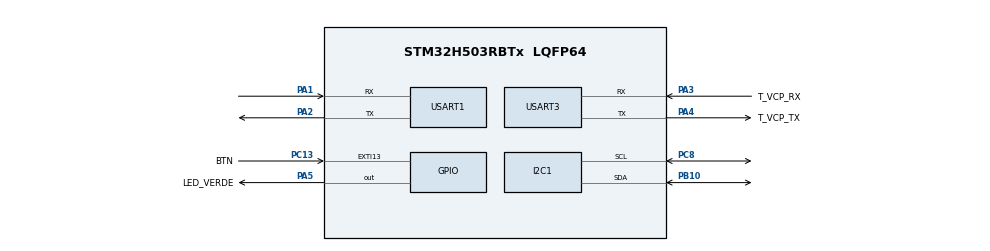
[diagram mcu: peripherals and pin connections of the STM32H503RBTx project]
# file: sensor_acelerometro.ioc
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BOOTPATH.BootPathName=LEGACY
BOOTPATH.UserSelectedBootPath=LEGACY
I2C1.Timing=0x10707DBC
Mcu.Family=STM32H5
Mcu.Name=STM32H503RBTx
Mcu.Package=LQFP64
NVIC.I2C1_ER_IRQn=true\:0\:0\:false\:false\:true\:true\:true\:true
NVIC.I2C1_EV_IRQn=true\:0\:0\:false\:false\:true\:true\:true\:true
NVIC.PriorityGroup=NVIC_PRIORITYGROUP_4
PA1.Mode=Asynchronous
PA1.Signal=USART1_RX
PA2.Mode=Asynchronous
PA2.Signal=USART1_TX
PA3.GPIO_Label=T_VCP_RX
PA3.Mode=Asynchronous
PA3.Signal=USART3_RX
PA4.GPIO_Label=T_VCP_TX
PA4.Mode=Asynchronous
PA4.Signal=USART3_TX
PA5.GPIO_Label=LED_VERDE
PA5.Signal=GPIO_Output
PB10.Mode=I2C
PB10.Signal=I2C1_SDA
PC13.GPIO_Label=BTN
PC13.Signal=GPXTI13
PC8.Mode=I2C
PC8.Signal=I2C1_SCL
ProjectManager.HeapSize=0x200
ProjectManager.StackSize=0x400
ProjectManager.TargetToolchain=STM32CubeIDE
RCC.ADCFreq_Value=64000000
RCC.AHBFreq_Value=64000000
RCC.APB1Freq_Value=64000000
RCC.APB1TimFreq_Value=64000000
RCC.APB2Freq_Value=64000000
RCC.APB2TimFreq_Value=64000000
RCC.APB3Freq_Value=64000000
RCC.CSI_VALUE=4000000
RCC.CortexFreq_Value=64000000
RCC.EPOD_VALUE=4000000
RCC.HCLKFreq_Value=64000000
RCC.HSE_VALUE=24000000
RCC.HSI48_VALUE=48000000
RCC.HSIDiv=RCC_HSI_DIV1
RCC.HSI_VALUE=64000000
RCC.LSE_VALUE=32768
RCC.LSIRC_VALUE=32000
RCC.PLLN=32
RCC.SYSCLKFreq_VALUE=64000000
RCC.USBFreq_Value=48000000
RCC.VCOOutputFreq_Value=128000000
USART1.VirtualMode-Asynchronous=VM_ASYNC
USART3.VirtualMode-Asynchronous=VM_ASYNC
VP_BOOTPATH_VS_BOOTPATH.Mode=BP_Activate
VP_CORTEX_M33_NS_VS_Hclk.Mode=Hclk_Mode
VP_MEMORYMAP_VS_MEMORYMAP.Mode=CurAppReg
VP_PWR_VS_DBSignals.Mode=DisableDeadBatterySignals
VP_PWR_VS_LPOM.Mode=PowerOptimisation
VP_PWR_VS_SECSignals.Mode=Security/Privilege
board=NUCLEO-H503RB

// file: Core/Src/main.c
/* USER CODE BEGIN Header */
/**
  ******************************************************************************
  * @file           : main.c
  * @brief          : Main program body
  ******************************************************************************
  * @attention
  *
  * Copyright (c) 2025 STMicroelectronics.
  * All rights reserved.
  *
  * This software is licensed under terms that can be found in the LICENSE file
  * in the root directory of this software component.
  * If no LICENSE file comes with this software, it is provided AS-IS.
  *
  ******************************************************************************
  */
/* USER CODE END Header */
#include "main.h"

/* USER CODE BEGIN Includes */
#include "stdbool.h"
/* USER CODE END Includes */

/* USER CODE BEGIN PTD */
#define BUFFER_MAX_USART 100

#define ADXL345_ADDR       0x53<<1  //Dirección I2C
#define REG_DEVID          0x00
#define REG_POWER_CTL      0x2D
#define REG_DATA_FORMAT    0x31
#define REG_BW_RATE        0x2C
#define REG_DATAX0         0x32
#define REG_DATAX1         0x33
#define REG_DATAY0         0x34
#define REG_DATAY1         0x35
#define REG_DATAZ0         0x36
#define REG_DATAZ1         0x37

#define REG_THRESH_ACT     0x24
#define REG_INT_ENABLE     0x2E
#define REG_INT_SOURCE     0x30

typedef struct{
	uint8_t bytes [BUFFER_MAX_USART];
	uint16_t longitud;
}Transfer_Config;

typedef struct{
	volatile float x_axis;
	volatile float y_axis;
	volatile float z_axis;
	volatile float acelX_filtrada;
	volatile float acelY_filtrada;
	volatile float acelZ_filtrada;
	bool startMeasure;
} Device_Config;

typedef struct{
	uint8_t ID;
	bool deviceReady;
	uint8_t rawData[8];
	int16_t rawX;
	int16_t rawY;
	int16_t rawZ;
} ADXL_Config;

typedef struct{
	uint8_t data_format;
	uint8_t power_ctl;
	uint8_t bw_rate;
} Values_ADXL;

Device_Config datos={};
ADXL_Config acelerometro={};
Values_ADXL values={};
Transfer_Config tx={};

void ADXL_Init(void);
void Value_Conversion(void);
void Send_USART(void);
float filtroSuavizado(float nuevo, float anterior);

/* USER CODE END PTD */

I2C_HandleTypeDef hi2c1;

UART_HandleTypeDef huart1;
UART_HandleTypeDef huart3;

void SystemClock_Config(void);
static void MX_GPIO_Init(void);
static void MX_I2C1_Init(void);
static void MX_USART3_UART_Init(void);
static void MX_USART1_UART_Init(void);

int main(void)
{

  /* MCU Configuration--------------------------------------------------------*/

  /* Reset of all peripherals, Initializes the Flash interface and the Systick. */
  HAL_Init();

  /* Configure the system clock */
  SystemClock_Config();

  /* Initialize all configured peripherals */
  MX_GPIO_Init();
  MX_I2C1_Init();
  MX_USART3_UART_Init();
  MX_USART1_UART_Init();
  /* USER CODE BEGIN 2 */

  datos.startMeasure=false;
  datos.x_axis=0;
  datos.y_axis=0;
  datos.z_axis=0;
  datos.acelX_filtrada=0;
  datos.acelY_filtrada=0;
  datos.acelZ_filtrada=0;

  //confirmacion de que existe acelerometro
  HAL_I2C_Mem_Read(&hi2c1, ADXL345_ADDR, REG_DEVID, 1, &acelerometro.ID, 1, 100);
  if (acelerometro.ID==0xE5) {
	  acelerometro.deviceReady=true;
  } else{
	  acelerometro.deviceReady=false;
  }

  //configuracion de acelerometro
  if(acelerometro.deviceReady){
	  ADXL_Init();
  }

  /* USER CODE END 2 */

  /* Infinite loop */
  /* USER CODE BEGIN WHILE */
  while (1)
  {
	  //obtencion de datos crudos
	    uint8_t buffer[2];

	    // Leer X
	    HAL_I2C_Mem_Read(&hi2c1, ADXL345_ADDR, REG_DATAX0, 1, buffer, 2, 100);
	    acelerometro.rawX = (buffer[1] << 8 | buffer[0]);

	    // Leer Y
	    HAL_I2C_Mem_Read(&hi2c1, ADXL345_ADDR, REG_DATAY0, 1, buffer, 2, 100);
	    acelerometro.rawY =(buffer[1] << 8 | buffer[0]);

	    //Leer Z
	    HAL_I2C_Mem_Read(&hi2c1, ADXL345_ADDR, REG_DATAZ0, 1, buffer, 2, 100);
	    acelerometro.rawZ = (buffer[1] << 8 | buffer[0]);

	    Value_Conversion();
	    Send_USART();

	    datos.acelX_filtrada = filtroSuavizado(datos.x_axis, datos.acelX_filtrada);
	    datos.acelY_filtrada = filtroSuavizado(datos.y_axis, datos.acelY_filtrada);
	    datos.acelZ_filtrada = filtroSuavizado(datos.z_axis, datos.acelZ_filtrada);

	    float magnitud = sqrt(pow(datos.acelX_filtrada,2) + pow(datos.acelY_filtrada,2) + pow(datos.acelZ_filtrada,2));

	    if (magnitud > 1.3 && magnitud < 2.0) {
	        snprintf((char*)tx.bytes, sizeof(tx.bytes), "Temblor leve detectado\r\n");
	        HAL_UART_Transmit(&huart3, tx.bytes, strlen((char*)tx.bytes), 1000);
	        HAL_UART_Transmit(&huart1, tx.bytes, strlen((char*)tx.bytes), 1000);

	    }
	    else if (magnitud >= 2.0) {
	        snprintf((char*)tx.bytes, sizeof(tx.bytes), "Temblor fuerte detectado\r\n");
	        HAL_UART_Transmit(&huart3, tx.bytes, strlen((char*)tx.bytes), 1000);
	        HAL_UART_Transmit(&huart1, tx.bytes, strlen((char*)tx.bytes), 1000);
	    }

    /* USER CODE END WHILE */

  }
}

void SystemClock_Config(void)
{
  RCC_OscInitTypeDef RCC_OscInitStruct = {0};
  RCC_ClkInitTypeDef RCC_ClkInitStruct = {0};

  /** Configure the main internal regulator output voltage
  */
  __HAL_PWR_VOLTAGESCALING_CONFIG(PWR_REGULATOR_VOLTAGE_SCALE3);

  while(!__HAL_PWR_GET_FLAG(PWR_FLAG_VOSRDY)) {}

  /** Initializes the RCC Oscillators according to the specified parameters
  * in the RCC_OscInitTypeDef structure.
  */
  RCC_OscInitStruct.OscillatorType = RCC_OSCILLATORTYPE_CSI;
  RCC_OscInitStruct.CSIState = RCC_CSI_ON;
  RCC_OscInitStruct.CSICalibrationValue = RCC_CSICALIBRATION_DEFAULT;
  RCC_OscInitStruct.PLL.PLLState = RCC_PLL_ON;
  RCC_OscInitStruct.PLL.PLLSource = RCC_PLL1_SOURCE_CSI;
  RCC_OscInitStruct.PLL.PLLM = 1;
  RCC_OscInitStruct.PLL.PLLN = 50;
  RCC_OscInitStruct.PLL.PLLP = 2;
  RCC_OscInitStruct.PLL.PLLQ = 2;
  RCC_OscInitStruct.PLL.PLLR = 2;
  RCC_OscInitStruct.PLL.PLLRGE = RCC_PLL1_VCIRANGE_2;
  RCC_OscInitStruct.PLL.PLLVCOSEL = RCC_PLL1_VCORANGE_WIDE;
  RCC_OscInitStruct.PLL.PLLFRACN = 0;
  if (HAL_RCC_OscConfig(&RCC_OscInitStruct) != HAL_OK)
  {
    Error_Handler();
  }

  /** Initializes the CPU, AHB and APB buses clocks
  */
  RCC_ClkInitStruct.ClockType = RCC_CLOCKTYPE_HCLK|RCC_CLOCKTYPE_SYSCLK
                              |RCC_CLOCKTYPE_PCLK1|RCC_CLOCKTYPE_PCLK2
                              |RCC_CLOCKTYPE_PCLK3;
  RCC_ClkInitStruct.SYSCLKSource = RCC_SYSCLKSOURCE_PLLCLK;
  RCC_ClkInitStruct.AHBCLKDivider = RCC_SYSCLK_DIV1;
  RCC_ClkInitStruct.APB1CLKDivider = RCC_HCLK_DIV1;
  RCC_ClkInitStruct.APB2CLKDivider = RCC_HCLK_DIV1;
  RCC_ClkInitStruct.APB3CLKDivider = RCC_HCLK_DIV1;

  if (HAL_RCC_ClockConfig(&RCC_ClkInitStruct, FLASH_LATENCY_4) != HAL_OK)
  {
    Error_Handler();
  }

  /** Configure the programming delay
  */
  __HAL_FLASH_SET_PROGRAM_DELAY(FLASH_PROGRAMMING_DELAY_2);
}

static void MX_I2C1_Init(void)
{

  hi2c1.Instance = I2C1;
  hi2c1.Init.Timing = 0x10C0ECFF;
  hi2c1.Init.OwnAddress1 = 0;
  hi2c1.Init.AddressingMode = I2C_ADDRESSINGMODE_7BIT;
  hi2c1.Init.DualAddressMode = I2C_DUALADDRESS_DISABLE;
  hi2c1.Init.OwnAddress2 = 0;
  hi2c1.Init.OwnAddress2Masks = I2C_OA2_NOMASK;
  hi2c1.Init.GeneralCallMode = I2C_GENERALCALL_DISABLE;
  hi2c1.Init.NoStretchMode = I2C_NOSTRETCH_DISABLE;
  if (HAL_I2C_Init(&hi2c1) != HAL_OK)
  {
    Error_Handler();
  }

  /** Configure Analogue filter
  */
  if (HAL_I2CEx_ConfigAnalogFilter(&hi2c1, I2C_ANALOGFILTER_ENABLE) != HAL_OK)
  {
    Error_Handler();
  }

  /** Configure Digital filter
  */
  if (HAL_I2CEx_ConfigDigitalFilter(&hi2c1, 0) != HAL_OK)
  {
    Error_Handler();
  }

}

static void MX_USART1_UART_Init(void)
{

  huart1.Instance = USART1;
  huart1.Init.BaudRate = 115200;
  huart1.Init.WordLength = UART_WORDLENGTH_8B;
  huart1.Init.StopBits = UART_STOPBITS_1;
  huart1.Init.Parity = UART_PARITY_NONE;
  huart1.Init.Mode = UART_MODE_TX_RX;
  huart1.Init.HwFlowCtl = UART_HWCONTROL_NONE;
  huart1.Init.OverSampling = UART_OVERSAMPLING_16;
  huart1.Init.OneBitSampling = UART_ONE_BIT_SAMPLE_DISABLE;
  huart1.Init.ClockPrescaler = UART_PRESCALER_DIV1;
  huart1.AdvancedInit.AdvFeatureInit = UART_ADVFEATURE_NO_INIT;
  if (HAL_UART_Init(&huart1) != HAL_OK)
  {
    Error_Handler();
  }
  if (HAL_UARTEx_SetTxFifoThreshold(&huart1, UART_TXFIFO_THRESHOLD_1_8) != HAL_OK)
  {
    Error_Handler();
  }
  if (HAL_UARTEx_SetRxFifoThreshold(&huart1, UART_RXFIFO_THRESHOLD_1_8) != HAL_OK)
  {
    Error_Handler();
  }
  if (HAL_UARTEx_DisableFifoMode(&huart1) != HAL_OK)
  {
    Error_Handler();
  }

}

static void MX_USART3_UART_Init(void)
{

  huart3.Instance = USART3;
  huart3.Init.BaudRate = 115200;
  huart3.Init.WordLength = UART_WORDLENGTH_8B;
  huart3.Init.StopBits = UART_STOPBITS_1;
  huart3.Init.Parity = UART_PARITY_NONE;
  huart3.Init.Mode = UART_MODE_TX_RX;
  huart3.Init.HwFlowCtl = UART_HWCONTROL_NONE;
  huart3.Init.OverSampling = UART_OVERSAMPLING_16;
  huart3.Init.OneBitSampling = UART_ONE_BIT_SAMPLE_DISABLE;
  huart3.Init.ClockPrescaler = UART_PRESCALER_DIV1;
  huart3.AdvancedInit.AdvFeatureInit = UART_ADVFEATURE_NO_INIT;
  if (HAL_UART_Init(&huart3) != HAL_OK)
  {
    Error_Handler();
  }
  if (HAL_UARTEx_SetTxFifoThreshold(&huart3, UART_TXFIFO_THRESHOLD_1_8) != HAL_OK)
  {
    Error_Handler();
  }
  if (HAL_UARTEx_SetRxFifoThreshold(&huart3, UART_RXFIFO_THRESHOLD_1_8) != HAL_OK)
  {
    Error_Handler();
  }
  if (HAL_UARTEx_DisableFifoMode(&huart3) != HAL_OK)
  {
    Error_Handler();
  }

}

static void MX_GPIO_Init(void)
{
  GPIO_InitTypeDef GPIO_InitStruct = {0};

  /* GPIO Ports Clock Enable */
  __HAL_RCC_GPIOC_CLK_ENABLE();
  __HAL_RCC_GPIOA_CLK_ENABLE();
  __HAL_RCC_GPIOB_CLK_ENABLE();

  /*Configure GPIO pin Output Level */
  HAL_GPIO_WritePin(LED_VERDE_GPIO_Port, LED_VERDE_Pin, GPIO_PIN_RESET);

  /*Configure GPIO pin : BTN_Pin */
  GPIO_InitStruct.Pin = BTN_Pin;
  GPIO_InitStruct.Mode = GPIO_MODE_IT_RISING;
  GPIO_InitStruct.Pull = GPIO_NOPULL;
  HAL_GPIO_Init(BTN_GPIO_Port, &GPIO_InitStruct);

  /*Configure GPIO pin : LED_VERDE_Pin */
  GPIO_InitStruct.Pin = LED_VERDE_Pin;
  GPIO_InitStruct.Mode = GPIO_MODE_OUTPUT_PP;
  GPIO_InitStruct.Pull = GPIO_NOPULL;
  GPIO_InitStruct.Speed = GPIO_SPEED_FREQ_LOW;
  HAL_GPIO_Init(LED_VERDE_GPIO_Port, &GPIO_InitStruct);

}

/* USER CODE BEGIN 4 */

//FUNCIONEEEEEEEEEESSS
void ADXL_Init(void){
	  values.bw_rate=0x0A; //100MHZ
	  values.data_format=0x00; //Rango +2g
	  values.power_ctl=0x08; //medicion activado

	  HAL_I2C_Mem_Write(&hi2c1, ADXL345_ADDR, REG_POWER_CTL, 1, &values.power_ctl, 1, 100);
	  HAL_I2C_Mem_Write(&hi2c1, ADXL345_ADDR, REG_DATA_FORMAT, 1, &values.data_format, 1, 100);
	  HAL_I2C_Mem_Write(&hi2c1, ADXL345_ADDR, REG_BW_RATE, 1, &values.bw_rate, 1, 100);
}

void Value_Conversion(void){
	datos.x_axis = acelerometro.rawX / 256.0;
	datos.y_axis = acelerometro.rawY / 256.0;
	datos.z_axis = acelerometro.rawZ / 256.0;
}

void Send_USART() {
    tx.longitud = (uint16_t)snprintf(
        (char*)tx.bytes,               // destino
        sizeof(tx.bytes),              // tamaño del buffer
        "X: %.2f  Y: %.2f  Z: %.2f\r\n", // formato con dos decimales
        (double)datos.x_axis,
        (double)datos.y_axis,
        (double)datos.z_axis
    );

    HAL_UART_Transmit(&huart3, tx.bytes, tx.longitud, 1000);
    HAL_Delay(100);
}

float filtroSuavizado(float nuevo, float anterior) {
    return 0.8 * anterior + 0.2 * nuevo;  // Filtro paso bajo
}

/* USER CODE END 4 */

void Error_Handler(void)
{
  __disable_irq();
  while (1)
  {
  }
}
